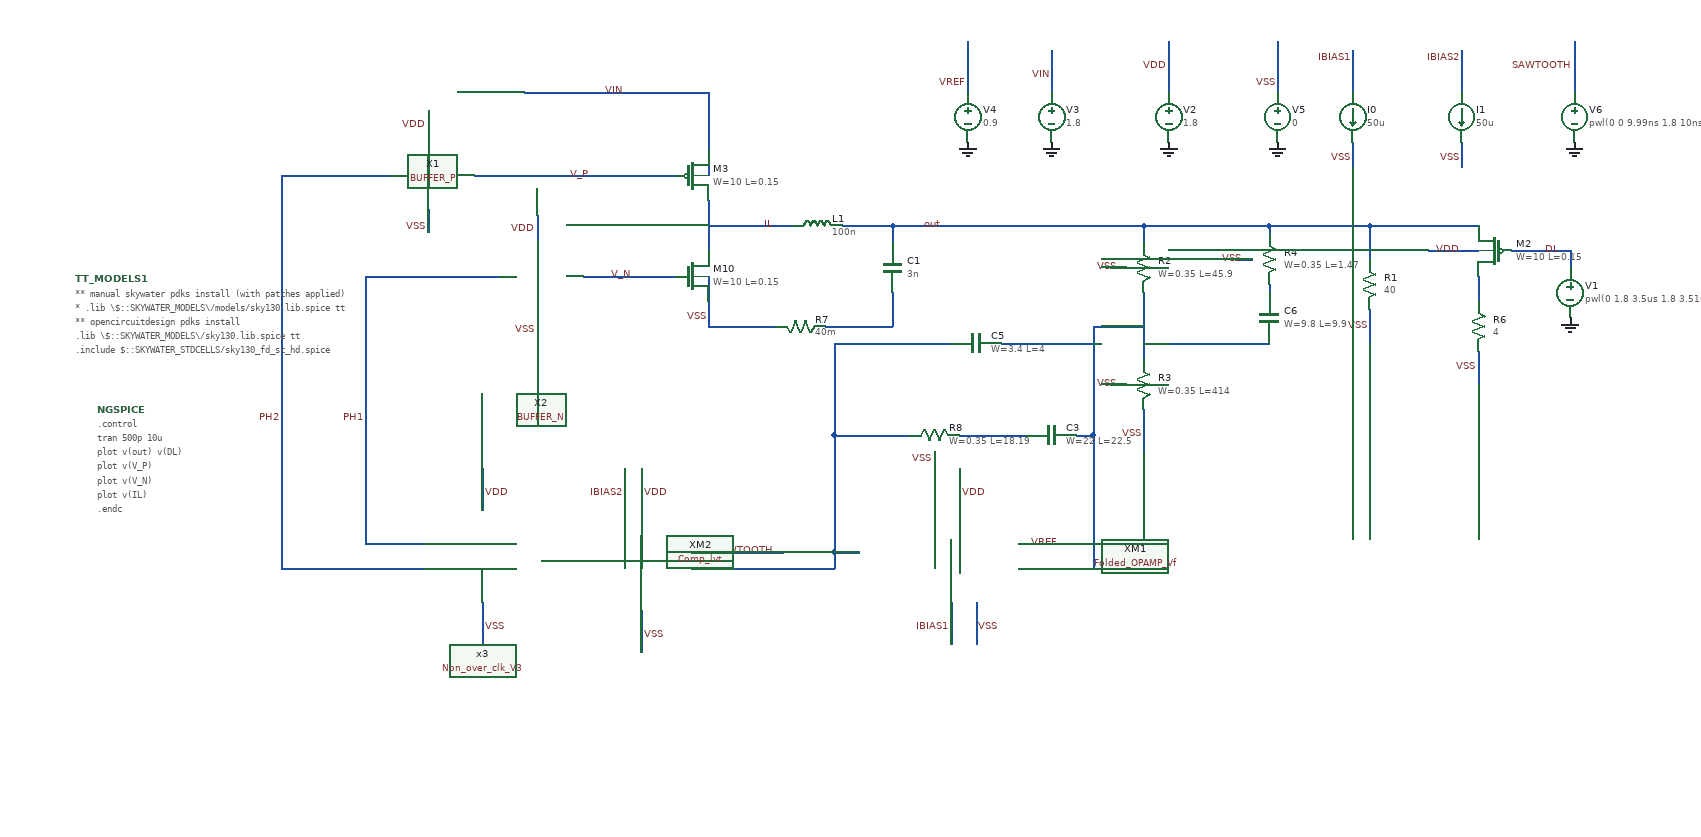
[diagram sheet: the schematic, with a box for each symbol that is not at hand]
v {xschem version=3.0.0 file_version=1.2 }
G {}
K {}
V {}
S {}
E {}
N 3080 -1560 3080 -1500 {
lab=IL}
N 3080 -1620 3080 -1590 {
lab=VIN}
N 2990 -1590 3040 -1590 {
lab=V_P}
N 3080 -1690 3080 -1620 {
lab=VIN}
N 2860 -1690 3080 -1690 {
lab=VIN}
N 3080 -1440 3080 -1410 {
lab=VSS}
N 3080 -1530 3140 -1530 {
lab=IL}
N 3140 -1530 3180 -1530 {
lab=IL}
N 3300 -1530 3300 -1510 {
lab=out}
N 3240 -1530 3300 -1530 {
lab=out}
N 3300 -1450 3300 -1410 {
lab=#net1}
N 3300 -1530 3410 -1530 {
lab=out}
N 3380 -1240 3380 -1190 {
lab=VDD}
N 3400 -1080 3400 -1030 {
lab=VSS}
N 3370 -1080 3370 -1030 {
lab=IBIAS1}
N 3450 -1120 3500 -1120 {
lab=#net2}
N 3450 -1150 3500 -1150 {
lab=VREF}
N 3490 -1740 3490 -1690 {
lab=VIN}
N 3630 -1700 3630 -1690 {
lab=VDD}
N 3630 -1750 3630 -1700 {
lab=VDD}
N 3760 -1720 3760 -1700 {
lab=VSS}
N 3760 -1700 3760 -1690 {
lab=VSS}
N 3760 -1750 3760 -1720 {
lab=VSS}
N 3850 -1740 3850 -1680 {
lab=IBIAS1}
N 3000 -1240 3000 -1190 {
lab=VDD}
N 3000 -1070 3000 -1020 {
lab=VSS}
N 3390 -1720 3390 -1700 {
lab=VREF}
N 3390 -1700 3390 -1690 {
lab=VREF}
N 3390 -1750 3390 -1720 {
lab=VREF}
N 3500 -1120 3530 -1120 {
lab=#net2}
N 2980 -1240 2980 -1190 {
lab=IBIAS2}
N 4115 -1750 4115 -1690 {
lab=SAWTOOTH}
N 2800 -1590 2990 -1590 {
lab=V_P}
N 3410 -1530 3590 -1530 {
lab=out}
N 3600 -1530 3600 -1510 {
lab=out}
N 3600 -1450 3600 -1400 {
lab=#net2}
N 3600 -1310 3600 -1260 {
lab=VSS}
N 3380 -1280 3460 -1280 {
lab=#net3}
N 3230 -1280 3320 -1280 {
lab=#net4}
N 3230 -1280 3230 -1140 {
lab=#net4}
N 3540 -1280 3540 -1150 {
lab=#net2}
N 3520 -1280 3540 -1280 {
lab=#net2}
N 3230 -1390 3370 -1390 {
lab=#net4}
N 3430 -1390 3540 -1390 {
lab=#net2}
N 3540 -1350 3540 -1280 {
lab=#net2}
N 3230 -1140 3260 -1140 {
lab=#net4}
N 3540 -1150 3540 -1120 {
lab=#net2}
N 3530 -1120 3540 -1120 {
lab=#net2}
N 3600 -1530 3750 -1530 {
lab=out}
N 3750 -1530 3750 -1520 {
lab=out}
N 3750 -1460 3750 -1450 {
lab=#net5}
N 3590 -1530 3600 -1530 {
lab=out}
N 3540 -1410 3540 -1350 {
lab=#net2}
N 3540 -1410 3600 -1410 {
lab=#net2}
N 3600 -1400 3600 -1370 {
lab=#net2}
N 3870 -1530 3870 -1490 {
lab=out}
N 3750 -1530 3870 -1530 {
lab=out}
N 3870 -1430 3870 -1390 {
lab=VSS}
N 3060 -1120 3230 -1120 {
lab=#net4}
N 3230 -1140 3230 -1120 {
lab=#net4}
N 2990 -1470 3040 -1470 {
lab=V_N}
N 3080 -1470 3080 -1440 {
lab=VSS}
N 3870 -1530 4000 -1530 {
lab=out}
N 4000 -1380 4000 -1340 {
lab=VSS}
N 4000 -1470 4000 -1440 {
lab=#net6}
N 4040 -1500 4110 -1500 {
lab=DL}
N 4110 -1500 4110 -1480 {
lab=DL}
N 2810 -1240 2810 -1190 {
lab=VDD}
N 2810 -1080 2810 -1030 {
lab=VSS}
N 2570 -1590 2700 -1590 {
lab=PH2}
N 2570 -1590 2570 -1150 {
lab=PH2}
N 2745 -1550 2745 -1522.5 {
lab=VSS}
N 2745 -1667.5 2745 -1632.5 {
lab=VDD}
N 2930 -1470 2990 -1470 {
lab=V_N}
N 2670 -1470 2830 -1470 {
lab=PH1}
N 2670 -1470 2670 -1380 {
lab=PH1}
N 2875 -1430 2875 -1392.5 {
lab=VSS}
N 2875 -1542.5 2875 -1512.5 {
lab=VDD}
N 2670 -1150 2730 -1150 {
lab=PH1}
N 2670 -1380 2670 -1150 {
lab=PH1}
N 2570 -1120 2730 -1120 {
lab=PH2}
N 2570 -1150 2570 -1120 {
lab=PH2}
N 3230 -1390 3230 -1280 {
lab=#net4}
N 3600 -1390 3650 -1390 {
lab=#net2}
N 3650 -1390 3750 -1390 {
lab=#net2}
N 3400 -1080 3400 -1030 {
lab=VSS}
N 3940 -1500 4000 -1500 {
lab=VDD}
N 3060 -1140 3170 -1140 {
lab=SAWTOOTH}
N 3350 -1260 3350 -1240 {
lab=VSS}
N 3710 -1490 3730 -1490 {
lab=VSS}
N 3560 -1480 3580 -1480 {
lab=VSS}
N 3560 -1340 3580 -1340 {
lab=VSS}
N 3270 -1410 3300 -1410 {
lab=#net1}
N 2730 -1150 2740 -1150 {
lab=PH1}
N 2730 -1120 2740 -1120 {
lab=PH2}
N 3080 -1410 3160 -1410 {
lab=VSS}
N 3220 -1410 3270 -1410 {
lab=#net1}
N 2890 -1130 2930 -1130 {
lab=#net7}
N 3980 -1740 3980 -1680 {
lab=IBIAS2}
N 3850 -1630 3850 -1610 {
lab=VSS}
N 3980 -1630 3980 -1610 {
lab=VSS}
N 3850 -1610 3850 -1600 {
lab=VSS}
N 3980 -1610 3980 -1600 {
lab=VSS}
N 2880 -1130 2890 -1130 {
lab=#net7}
N 3500 -1150 3510 -1150 {
lab=VREF}
C {sky130_fd_pr/pfet_01v8.sym} 3060 -1590 0 0 {name=M3
L=0.15
W=10
nf=1
mult=450
ad="'int((nf+1)/2) * W/nf * 0.29'" 
pd="'2*int((nf+1)/2) * (W/nf + 0.29)'"
as="'int((nf+2)/2) * W/nf * 0.29'" 
ps="'2*int((nf+2)/2) * (W/nf + 0.29)'"
nrd="'0.29 / W'" nrs="'0.29 / W'"
sa=0 sb=0 sd=0
model=pfet_01v8
spiceprefix=X
}
C {devices/ind.sym} 3210 -1530 3 0 {name=L1
m=1
value=100n
footprint=1206
device=inductor}
C {devices/capa.sym} 3300 -1480 0 0 {name=C1
m=1
value=3n
footprint=1206
device="ceramic capacitor"}
C {devices/code_shown.sym} 2350 -1310 0 0 {name=NGSPICE
only_toplevel=true
value="

.control

tran 500p 10u
plot  v(out) v(DL)
plot v(V_P) 
plot v(V_N)
plot v(IL)
.endc
" }
C {devices/lab_wire.sym} 3360 -1530 0 0 {name=l4 sig_type=std_logic lab=out}
C {devices/lab_wire.sym} 3160 -1530 0 0 {name=l6 sig_type=std_logic lab=IL}
C {devices/lab_wire.sym} 2980 -1690 0 0 {name=l5 sig_type=std_logic lab=VIN}
C {devices/vsource.sym} 3490 -1660 0 0 {name=V3 value=1.8}
C {devices/gnd.sym} 3490 -1630 0 0 {name=l7 lab=GND}
C {devices/lab_wire.sym} 3490 -1710 0 0 {name=l2 sig_type=std_logic lab=VIN}
C {devices/lab_wire.sym} 3850 -1730 0 0 {name=l22 sig_type=std_logic lab=IBIAS1}
C {devices/isource.sym} 3850 -1660 0 0 {name=I0 value=50u}
C {devices/vsource.sym} 3630 -1660 0 0 {name=V2 value=1.8}
C {devices/gnd.sym} 3630 -1630 0 0 {name=l18 lab=GND}
C {devices/vsource.sym} 3760 -1660 0 0 {name=V5 value=0}
C {devices/gnd.sym} 3760 -1630 0 0 {name=l26 lab=GND}
C {devices/lab_wire.sym} 3760 -1700 0 0 {name=l10 sig_type=std_logic lab=VSS}
C {devices/lab_wire.sym} 3380 -1210 0 1 {name=l13 sig_type=std_logic lab=VDD}
C {devices/lab_wire.sym} 3080 -1420 0 0 {name=l1 sig_type=std_logic lab=VSS}
C {devices/lab_wire.sym} 3400 -1050 0 1 {name=l15 sig_type=std_logic lab=VSS}
C {devices/lab_wire.sym} 3370 -1050 0 0 {name=l16 sig_type=std_logic lab=IBIAS1}
C {devices/lab_wire.sym} 3000 -1210 0 1 {name=l11 sig_type=std_logic lab=VDD}
C {devices/lab_wire.sym} 3000 -1040 0 1 {name=l12 sig_type=std_logic lab=VSS}
C {devices/vsource.sym} 3390 -1660 0 0 {name=V4 value=0.9}
C {devices/gnd.sym} 3390 -1630 0 0 {name=l17 lab=GND}
C {devices/lab_wire.sym} 3390 -1700 0 0 {name=l20 sig_type=std_logic lab=VREF}
C {devices/lab_wire.sym} 2980 -1210 0 0 {name=l27 sig_type=std_logic lab=IBIAS2}
C {devices/vsource.sym} 4115 -1660 0 0 {name=V6 value="pwl(0 0 9.99ns 1.8 10ns 0) r=0"}
C {devices/gnd.sym} 4115 -1630 0 0 {name=l28 lab=GND}
C {devices/gnd.sym} 4115 -1630 0 0 {name=l29 lab=GND}
C {devices/lab_wire.sym} 4115 -1720 0 0 {name=l30 sig_type=std_logic lab=SAWTOOTH}
C {devices/lab_wire.sym} 3600 -1280 0 0 {name=l31 sig_type=std_logic lab=VSS}
C {devices/lab_wire.sym} 3500 -1150 0 0 {name=l33 sig_type=std_logic lab=VREF}
C {devices/lab_wire.sym} 3160 -1140 0 0 {name=l32 sig_type=std_logic lab=SAWTOOTH}
C {devices/lab_wire.sym} 3870 -1410 0 0 {name=l21 sig_type=std_logic lab=VSS}
C {sky130_fd_pr/pfet_01v8.sym} 4020 -1500 0 1 {name=M2
L=0.15
W=10
nf=1
mult=450
ad="'int((nf+1)/2) * W/nf * 0.29'" 
pd="'2*int((nf+1)/2) * (W/nf + 0.29)'"
as="'int((nf+2)/2) * W/nf * 0.29'" 
ps="'2*int((nf+2)/2) * (W/nf + 0.29)'"
nrd="'0.29 / W'" nrs="'0.29 / W'"
sa=0 sb=0 sd=0
model=pfet_01v8
spiceprefix=X
}
C {devices/lab_wire.sym} 4000 -1360 0 0 {name=l23 sig_type=std_logic lab=VSS}
C {devices/vsource.sym} 4110 -1450 0 0 {name=V1 value="pwl(0 1.8 3.5us 1.8 3.51us 0 7us 0) r=0"}
C {devices/gnd.sym} 4110 -1420 0 0 {name=l34 lab=GND}
C {devices/gnd.sym} 4110 -1420 0 0 {name=l36 lab=GND}
C {devices/lab_wire.sym} 2810 -1210 0 1 {name=l35 sig_type=std_logic lab=VDD}
C {devices/lab_wire.sym} 2810 -1050 0 1 {name=l37 sig_type=std_logic lab=VSS}
C {DC_DC_Converter/BUFFER/BUFFER_PMOS/BUFFER_P.sym} 2680 -1540 0 0 {name=X1}
C {devices/lab_wire.sym} 2745 -1650 0 0 {name=l38 sig_type=std_logic lab=VDD}
C {devices/lab_wire.sym} 2745 -1527.5 0 0 {name=l40 sig_type=std_logic lab=VSS}
C {devices/lab_wire.sym} 2875 -1405 0 0 {name=l39 sig_type=std_logic lab=VSS}
C {devices/lab_wire.sym} 2875 -1525 0 0 {name=l41 sig_type=std_logic lab=VDD}
C {devices/lab_wire.sym} 2940 -1590 0 0 {name=l3 sig_type=std_logic lab=V_P}
C {devices/lab_wire.sym} 2990 -1470 0 0 {name=l43 sig_type=std_logic lab=V_N}
C {devices/lab_wire.sym} 4100 -1500 0 0 {name=l96 sig_type=std_logic lab=DL}
C {sky130_fd_pr/cap_mim_m3_1.sym} 3400 -1390 3 0 {name=C5 model=cap_mim_m3_1 W=3.4 L=4 MF=1 spiceprefix=X}
C {sky130_fd_pr/cap_mim_m3_1.sym} 3490 -1280 3 0 {name=C3 model=cap_mim_m3_1 W=22 L=22.5 MF=1 spiceprefix=X}
C {sky130_fd_pr/cap_mim_m3_1.sym} 3750 -1420 0 0 {name=C6 model=cap_mim_m3_1 W=9.8 L=9.9 MF=1 spiceprefix=X}
C {devices/lab_wire.sym} 3630 -1720 0 0 {name=l97 sig_type=std_logic lab=VDD}
C {devices/lab_wire.sym} 3980 -1500 0 0 {name=l98 sig_type=std_logic lab=VDD}
C {sky130_fd_pr/nfet_01v8.sym} 3060 -1470 0 0 {name=M10
L=0.15
W=10
nf=1 
mult=150
ad="'int((nf+1)/2) * W/nf * 0.29'" 
pd="'2*int((nf+1)/2) * (W/nf + 0.29)'"
as="'int((nf+2)/2) * W/nf * 0.29'" 
ps="'2*int((nf+2)/2) * (W/nf + 0.29)'"
nrd="'0.29 / W'" nrs="'0.29 / W'"
sa=0 sb=0 sd=0
model=nfet_01v8
spiceprefix=X
}
C {DC_DC_Converter/Comparator/Comp_lvt.sym} 3080 -1060 0 1 {name=XM2}
C {devices/lab_wire.sym} 3350 -1250 3 0 {name=l9 sig_type=std_logic lab=VSS}
C {devices/lab_wire.sym} 3720 -1490 0 0 {name=l44 sig_type=std_logic lab=VSS}
C {devices/lab_wire.sym} 3570 -1480 0 0 {name=l45 sig_type=std_logic lab=VSS}
C {devices/lab_wire.sym} 3570 -1340 0 0 {name=l46 sig_type=std_logic lab=VSS}
C {devices/res.sym} 3190 -1410 1 0 {name=R7
value=40m
footprint=1206
device=resistor
m=1}
C {devices/res.sym} 3870 -1460 0 0 {name=R1
value=40
footprint=1206
device=resistor
m=1}
C {devices/res.sym} 4000 -1410 0 0 {name=R6
value=4
footprint=1206
device=resistor
m=1}
C {DC_DC_Converter/BUFFER/BUFFER_NMOS/BUFFER_N.sym} 2740 -1390 0 0 {name=X2}
C {sky130_fd_pr/res_xhigh_po_0p35.sym} 3350 -1280 3 0 {name=R8
W=0.35
L=18.19
model=res_xhigh_po_0p35
spiceprefix=X
mult=1}
C {sky130_fd_pr/res_xhigh_po_0p35.sym} 3600 -1480 0 0 {name=R2
W=0.35
L=45.9
model=res_xhigh_po_0p35
spiceprefix=X
mult=1}
C {sky130_fd_pr/res_xhigh_po_0p35.sym} 3600 -1340 0 0 {name=R3
W=0.35
L=414
model=res_xhigh_po_0p35
spiceprefix=X
mult=1}
C {devices/code.sym} 2323 -1466 0 0 {name=TT_MODELS1
only_toplevel=true
format="tcleval(@value )"
value="** manual skywater pdks install (with patches applied)
* .lib \\\\$::SKYWATER_MODELS\\\\/models/sky130.lib.spice tt

** opencircuitdesign pdks install
.lib \\\\$::SKYWATER_MODELS\\\\/sky130.lib.spice tt
.include $::SKYWATER_STDCELLS/sky130_fd_sc_hd.spice
"
spice_ignore=false}
C {devices/lab_wire.sym} 3980 -1730 0 0 {name=l25 sig_type=std_logic lab=IBIAS2}
C {devices/isource.sym} 3980 -1660 0 0 {name=I1 value=50u}
C {devices/lab_wire.sym} 2670 -1300 0 0 {name=l47 sig_type=std_logic lab=PH1}
C {devices/lab_wire.sym} 2570 -1300 0 0 {name=l48 sig_type=std_logic lab=PH2}
C {devices/lab_wire.sym} 3980 -1610 0 0 {name=l19 sig_type=std_logic lab=VSS}
C {devices/lab_wire.sym} 3850 -1610 0 0 {name=l24 sig_type=std_logic lab=VSS}
C {sky130_fd_pr/res_xhigh_po_0p35.sym} 3750 -1490 0 0 {name=R4
W=0.35
L=1.47
model=res_xhigh_po_0p35
spiceprefix=X
mult=1}
C {OTHERS/DC_DC_Converter_V7/Non_Overlap_Clk/Non_over_clk_V3.sym} 3010 -870 0 1 {name=x3}
C {OTHERS/DC_DC_Converter_V7/Folded_OPAMP/Folded_OPAMP_Vf.sym} 3600 -970 0 1 {name=XM1}
